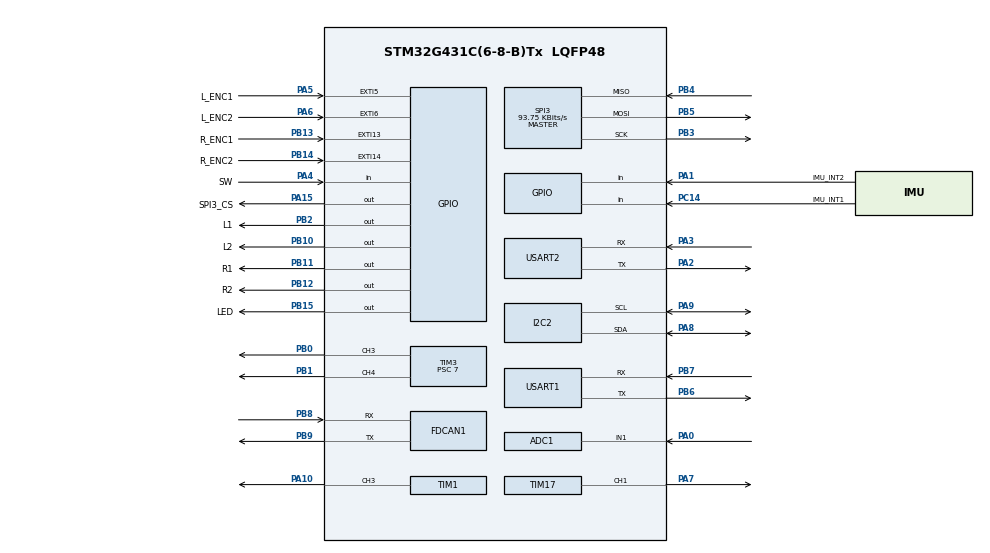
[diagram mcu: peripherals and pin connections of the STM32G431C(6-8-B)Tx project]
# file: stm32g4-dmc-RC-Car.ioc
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ADC1.Channel-2\#ChannelRegularConversion=ADC_CHANNEL_1
ADC1.NbrOfConversionFlag=1
ADC1.OffsetNumber-2\#ChannelRegularConversion=ADC_OFFSET_NONE
ADC1.Rank-2\#ChannelRegularConversion=1
ADC1.SamplingTime-2\#ChannelRegularConversion=ADC_SAMPLETIME_2CYCLES_5
ADC1.master=1
Dma.ADC1.2.Direction=DMA_PERIPH_TO_MEMORY
Dma.ADC1.2.EventEnable=DISABLE
Dma.ADC1.2.Instance=DMA1_Channel3
Dma.ADC1.2.MemDataAlignment=DMA_MDATAALIGN_HALFWORD
Dma.ADC1.2.MemInc=DMA_MINC_ENABLE
Dma.ADC1.2.Mode=DMA_NORMAL
Dma.ADC1.2.PeriphDataAlignment=DMA_PDATAALIGN_HALFWORD
Dma.ADC1.2.PeriphInc=DMA_PINC_DISABLE
Dma.ADC1.2.Polarity=HAL_DMAMUX_REQ_GEN_RISING
Dma.ADC1.2.Priority=DMA_PRIORITY_LOW
Dma.ADC1.2.RequestNumber=1
Dma.ADC1.2.SignalID=NONE
Dma.ADC1.2.SyncEnable=DISABLE
Dma.ADC1.2.SyncPolarity=HAL_DMAMUX_SYNC_NO_EVENT
Dma.ADC1.2.SyncRequestNumber=1
Dma.ADC1.2.SyncSignalID=NONE
Dma.Request0=USART1_RX
Dma.Request1=USART2_RX
Dma.Request2=ADC1
Dma.USART1_RX.0.Direction=DMA_PERIPH_TO_MEMORY
Dma.USART1_RX.0.EventEnable=DISABLE
Dma.USART1_RX.0.Instance=DMA1_Channel1
Dma.USART1_RX.0.MemDataAlignment=DMA_MDATAALIGN_BYTE
Dma.USART1_RX.0.MemInc=DMA_MINC_ENABLE
Dma.USART1_RX.0.Mode=DMA_CIRCULAR
Dma.USART1_RX.0.PeriphDataAlignment=DMA_PDATAALIGN_BYTE
Dma.USART1_RX.0.PeriphInc=DMA_PINC_DISABLE
Dma.USART1_RX.0.Polarity=HAL_DMAMUX_REQ_GEN_RISING
Dma.USART1_RX.0.Priority=DMA_PRIORITY_LOW
Dma.USART1_RX.0.RequestNumber=1
Dma.USART1_RX.0.SignalID=NONE
Dma.USART1_RX.0.SyncEnable=DISABLE
Dma.USART1_RX.0.SyncPolarity=HAL_DMAMUX_SYNC_NO_EVENT
Dma.USART1_RX.0.SyncRequestNumber=1
Dma.USART1_RX.0.SyncSignalID=NONE
Dma.USART2_RX.1.Direction=DMA_PERIPH_TO_MEMORY
Dma.USART2_RX.1.EventEnable=DISABLE
Dma.USART2_RX.1.Instance=DMA1_Channel2
Dma.USART2_RX.1.MemDataAlignment=DMA_MDATAALIGN_BYTE
Dma.USART2_RX.1.MemInc=DMA_MINC_ENABLE
Dma.USART2_RX.1.Mode=DMA_CIRCULAR
Dma.USART2_RX.1.PeriphDataAlignment=DMA_PDATAALIGN_BYTE
Dma.USART2_RX.1.PeriphInc=DMA_PINC_DISABLE
Dma.USART2_RX.1.Polarity=HAL_DMAMUX_REQ_GEN_RISING
Dma.USART2_RX.1.Priority=DMA_PRIORITY_LOW
Dma.USART2_RX.1.RequestNumber=1
Dma.USART2_RX.1.SignalID=NONE
Dma.USART2_RX.1.SyncEnable=DISABLE
Dma.USART2_RX.1.SyncPolarity=HAL_DMAMUX_SYNC_NO_EVENT
Dma.USART2_RX.1.SyncRequestNumber=1
Dma.USART2_RX.1.SyncSignalID=NONE
FDCAN1.CalculateBaudRateNominal=1000000
FDCAN1.CalculateTimeBitNominal=1000
FDCAN1.CalculateTimeQuantumNominal=333.3333333333333
I2C2.Timing=0x00805C87
Mcu.Family=STM32G4
Mcu.Name=STM32G431C(6-8-B)Tx
Mcu.Package=LQFP48
NVIC.EXTI15_10_IRQn=true\:0\:0\:false\:false\:true\:true\:true\:true
NVIC.EXTI9_5_IRQn=true\:0\:0\:false\:false\:true\:true\:true\:true
NVIC.FDCAN1_IT0_IRQn=true\:0\:0\:false\:false\:true\:true\:true\:true
NVIC.FDCAN1_IT1_IRQn=true\:0\:0\:false\:false\:true\:true\:true\:true
NVIC.PriorityGroup=NVIC_PRIORITYGROUP_4
PA0.Mode=IN1-Single-Ended
PA0.Signal=ADC1_IN1
PA1.GPIO_Label=IMU_INT2
PA1.GPIO_Mode=GPIO_MODE_INPUT
PA1.GPIO_PuPd=GPIO_NOPULL
PA1.Signal=GPIO_Input
PA10.Signal=S_TIM1_CH3
PA13.Mode=Serial_Wire
PA13.Signal=SYS_JTMS-SWDIO
PA14.Mode=Serial_Wire
PA14.Signal=SYS_JTCK-SWCLK
PA15.GPIO_Label=SPI3_CS
PA15.Signal=GPIO_Output
PA2.Mode=Asynchronous
PA2.Signal=USART2_TX
PA3.Mode=Asynchronous
PA3.Signal=USART2_RX
PA4.GPIO_Label=SW
PA4.GPIO_PuPd=GPIO_NOPULL
PA4.Signal=GPIO_Input
PA5.GPIO_Label=L_ENC1
PA5.GPIO_ModeDefaultEXTI=GPIO_MODE_IT_RISING_FALLING
PA5.GPIO_PuPd=GPIO_NOPULL
PA5.Signal=GPXTI5
PA6.GPIO_Label=L_ENC2
PA6.GPIO_ModeDefaultEXTI=GPIO_MODE_IT_RISING_FALLING
PA6.GPIO_PuPd=GPIO_NOPULL
PA6.Signal=GPXTI6
PA7.Signal=S_TIM17_CH1
PA8.Mode=I2C
PA8.Signal=I2C2_SDA
PA9.Mode=I2C
PA9.Signal=I2C2_SCL
PB0.Signal=S_TIM3_CH3
PB1.Signal=S_TIM3_CH4
PB10.GPIO_Label=L2
PB10.Signal=GPIO_Output
PB11.GPIO_Label=R1
PB11.Signal=GPIO_Output
PB12.GPIO_Label=R2
PB12.Signal=GPIO_Output
PB13.GPIO_Label=R_ENC1
PB13.GPIO_ModeDefaultEXTI=GPIO_MODE_IT_RISING_FALLING
PB13.GPIO_PuPd=GPIO_NOPULL
PB13.Signal=GPXTI13
PB14.GPIO_Label=R_ENC2
PB14.GPIO_ModeDefaultEXTI=GPIO_MODE_IT_RISING_FALLING
PB14.GPIO_PuPd=GPIO_NOPULL
PB14.Signal=GPXTI14
PB15.GPIO_Label=LED
PB15.PinState=GPIO_PIN_SET
PB15.Signal=GPIO_Output
PB2.GPIO_Label=L1
PB2.Signal=GPIO_Output
PB3.GPIO_Speed=GPIO_SPEED_FREQ_HIGH
PB3.Mode=Full_Duplex_Master
PB3.Signal=SPI3_SCK
PB4.Mode=Full_Duplex_Master
PB4.Signal=SPI3_MISO
PB5.GPIO_Speed=GPIO_SPEED_FREQ_HIGH
PB5.Mode=Full_Duplex_Master
PB5.Signal=SPI3_MOSI
PB6.Mode=Asynchronous
PB6.Signal=USART1_TX
PB7.Mode=Asynchronous
PB7.Signal=USART1_RX
PB8-BOOT0.Mode=FDCAN_Activate
PB8-BOOT0.Signal=FDCAN1_RX
PB9.Mode=FDCAN_Activate
PB9.Signal=FDCAN1_TX
PC14-OSC32_IN.GPIO_Label=IMU_INT1
PC14-OSC32_IN.Signal=GPIO_Input
PF0-OSC_IN.Mode=HSE-External-Oscillator
PF0-OSC_IN.Signal=RCC_OSC_IN
PF1-OSC_OUT.Mode=HSE-External-Oscillator
PF1-OSC_OUT.Signal=RCC_OSC_OUT
ProjectManager.HeapSize=0x200
ProjectManager.StackSize=0x400
ProjectManager.TargetToolchain=STM32CubeIDE
RCC.ADC12Freq_Value=48000000
RCC.AHBFreq_Value=48000000
RCC.APB1CLKDivider=RCC_HCLK_DIV2
RCC.APB1Freq_Value=24000000
RCC.APB1TimFreq_Value=48000000
RCC.APB2Freq_Value=48000000
RCC.APB2TimFreq_Value=48000000
RCC.CortexFreq_Value=48000000
RCC.EXTERNAL_CLOCK_VALUE=12288000
RCC.FDCANCLockSelection=RCC_FDCANCLKSOURCE_PLL
RCC.HCLKFreq_Value=48000000
RCC.HSE_VALUE=8000000
RCC.HSI48_VALUE=48000000
RCC.HSI_VALUE=16000000
RCC.LSE_VALUE=32768
RCC.PLLN=24
RCC.PLLQ=RCC_PLLQ_DIV4
RCC.PLLR=RCC_PLLR_DIV4
RCC.PLLSourceVirtual=RCC_PLLSOURCE_HSE
RCC.SYSCLKFreq_VALUE=48000000
RCC.SYSCLKSource=RCC_SYSCLKSOURCE_PLLCLK
RCC.USBFreq_Value=48000000
RCC.VCOOutputFreq_Value=192000000
SH.S_TIM17_CH1.0=TIM17_CH1,PWM Generation1 CH1
SH.S_TIM1_CH3.0=TIM1_CH3,PWM Generation3 CH3
SH.S_TIM3_CH3.0=TIM3_CH3,PWM Generation3 CH3
SH.S_TIM3_CH4.0=TIM3_CH4,PWM Generation4 CH4
SPI3.BaudRatePrescaler=SPI_BAUDRATEPRESCALER_256
SPI3.CLKPhase=SPI_PHASE_1EDGE
SPI3.CLKPolarity=SPI_POLARITY_LOW
SPI3.CRCCalculation=SPI_CRCCALCULATION_DISABLE
SPI3.CalculateBaudRate=93.75 KBits/s
SPI3.DataSize=SPI_DATASIZE_8BIT
SPI3.Direction=SPI_DIRECTION_2LINES
SPI3.FirstBit=SPI_FIRSTBIT_LSB
SPI3.Mode=SPI_MODE_MASTER
SPI3.TIMode=SPI_TIMODE_DISABLE
SPI3.VirtualType=VM_MASTER
TIM1.Channel-PWM\ Generation3\ CH3=TIM_CHANNEL_3
TIM1.PeriodNoDither=959
TIM1.Prescaler=999
TIM17.Channel=TIM_CHANNEL_1
TIM17.PeriodNoDither=959
TIM17.Prescaler=999
TIM3.Channel-PWM\ Generation3\ CH3=TIM_CHANNEL_3
TIM3.Channel-PWM\ Generation4\ CH4=TIM_CHANNEL_4
TIM3.PeriodNoDither=255
TIM3.Prescaler=7
USART1.VirtualMode-Asynchronous=VM_ASYNC
USART2.VirtualMode-Asynchronous=VM_ASYNC
VP_SYS_VS_DBSignals.Mode=DisableDeadBatterySignals
VP_TIM17_VS_ClockSourceINT.Mode=Enable_Timer
VP_TIM1_VS_ClockSourceINT.Mode=Internal
VP_TIM3_VS_ClockSourceINT.Mode=Internal
board=custom

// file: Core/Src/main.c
/* USER CODE BEGIN Header */
/**
  ******************************************************************************
  * @file           : main.c
  * @brief          : Main program body
  ******************************************************************************
  * @attention
  *
  * Copyright (c) 2024 STMicroelectronics.
  * All rights reserved.
  *
  * This software is licensed under terms that can be found in the LICENSE file
  * in the root directory of this software component.
  * If no LICENSE file comes with this software, it is provided AS-IS.
  *
  ******************************************************************************
  */
/* USER CODE END Header */
#include "main.h"
#include "adc.h"
#include "dma.h"
#include "fdcan.h"
#include "i2c.h"
#include "spi.h"
#include "tim.h"
#include "usart.h"
#include "gpio.h"

/* USER CODE BEGIN Includes */
#include "ap.h"
/* USER CODE END Includes */

void SystemClock_Config(void);

int main(void)
{

  /* MCU Configuration--------------------------------------------------------*/

  /* Reset of all peripherals, Initializes the Flash interface and the Systick. */
  HAL_Init();

  /* Configure the system clock */
  SystemClock_Config();

  /* Initialize all configured peripherals */
  MX_GPIO_Init();
  MX_DMA_Init();
  MX_USART1_UART_Init();
  MX_USART2_UART_Init();
  MX_FDCAN1_Init();
  MX_TIM3_Init();
  MX_I2C2_Init();
  MX_TIM1_Init();
  MX_TIM17_Init();
  MX_SPI3_Init();
  MX_ADC1_Init();
  /* USER CODE BEGIN 2 */

  hwInit();
  apInit();
  apMain();

  /* USER CODE END 2 */

  /* Infinite loop */
  while (1)
  {

  }
}

void SystemClock_Config(void)
{
  RCC_OscInitTypeDef RCC_OscInitStruct = {0};
  RCC_ClkInitTypeDef RCC_ClkInitStruct = {0};

  /** Configure the main internal regulator output voltage
  */
  HAL_PWREx_ControlVoltageScaling(PWR_REGULATOR_VOLTAGE_SCALE1_BOOST);

  /** Initializes the RCC Oscillators according to the specified parameters
  * in the RCC_OscInitTypeDef structure.
  */
  RCC_OscInitStruct.OscillatorType = RCC_OSCILLATORTYPE_HSE;
  RCC_OscInitStruct.HSEState = RCC_HSE_ON;
  RCC_OscInitStruct.PLL.PLLState = RCC_PLL_ON;
  RCC_OscInitStruct.PLL.PLLSource = RCC_PLLSOURCE_HSE;
  RCC_OscInitStruct.PLL.PLLM = RCC_PLLM_DIV1;
  RCC_OscInitStruct.PLL.PLLN = 40;
  RCC_OscInitStruct.PLL.PLLP = RCC_PLLP_DIV2;
  RCC_OscInitStruct.PLL.PLLQ = RCC_PLLQ_DIV4;
  RCC_OscInitStruct.PLL.PLLR = RCC_PLLR_DIV2;
  if (HAL_RCC_OscConfig(&RCC_OscInitStruct) != HAL_OK)
  {
    Error_Handler();
  }

  /** Initializes the CPU, AHB and APB buses clocks
  */
  RCC_ClkInitStruct.ClockType = RCC_CLOCKTYPE_HCLK|RCC_CLOCKTYPE_SYSCLK
                              |RCC_CLOCKTYPE_PCLK1|RCC_CLOCKTYPE_PCLK2;
  RCC_ClkInitStruct.SYSCLKSource = RCC_SYSCLKSOURCE_PLLCLK;
  RCC_ClkInitStruct.AHBCLKDivider = RCC_SYSCLK_DIV1;
  RCC_ClkInitStruct.APB1CLKDivider = RCC_HCLK_DIV1;
  RCC_ClkInitStruct.APB2CLKDivider = RCC_HCLK_DIV1;

  if (HAL_RCC_ClockConfig(&RCC_ClkInitStruct, FLASH_LATENCY_4) != HAL_OK)
  {
    Error_Handler();
  }
}

void Error_Handler(void)
{
  __disable_irq();
  while (1)
  {
  }
}
